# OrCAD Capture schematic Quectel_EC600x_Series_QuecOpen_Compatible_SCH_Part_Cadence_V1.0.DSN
size A1

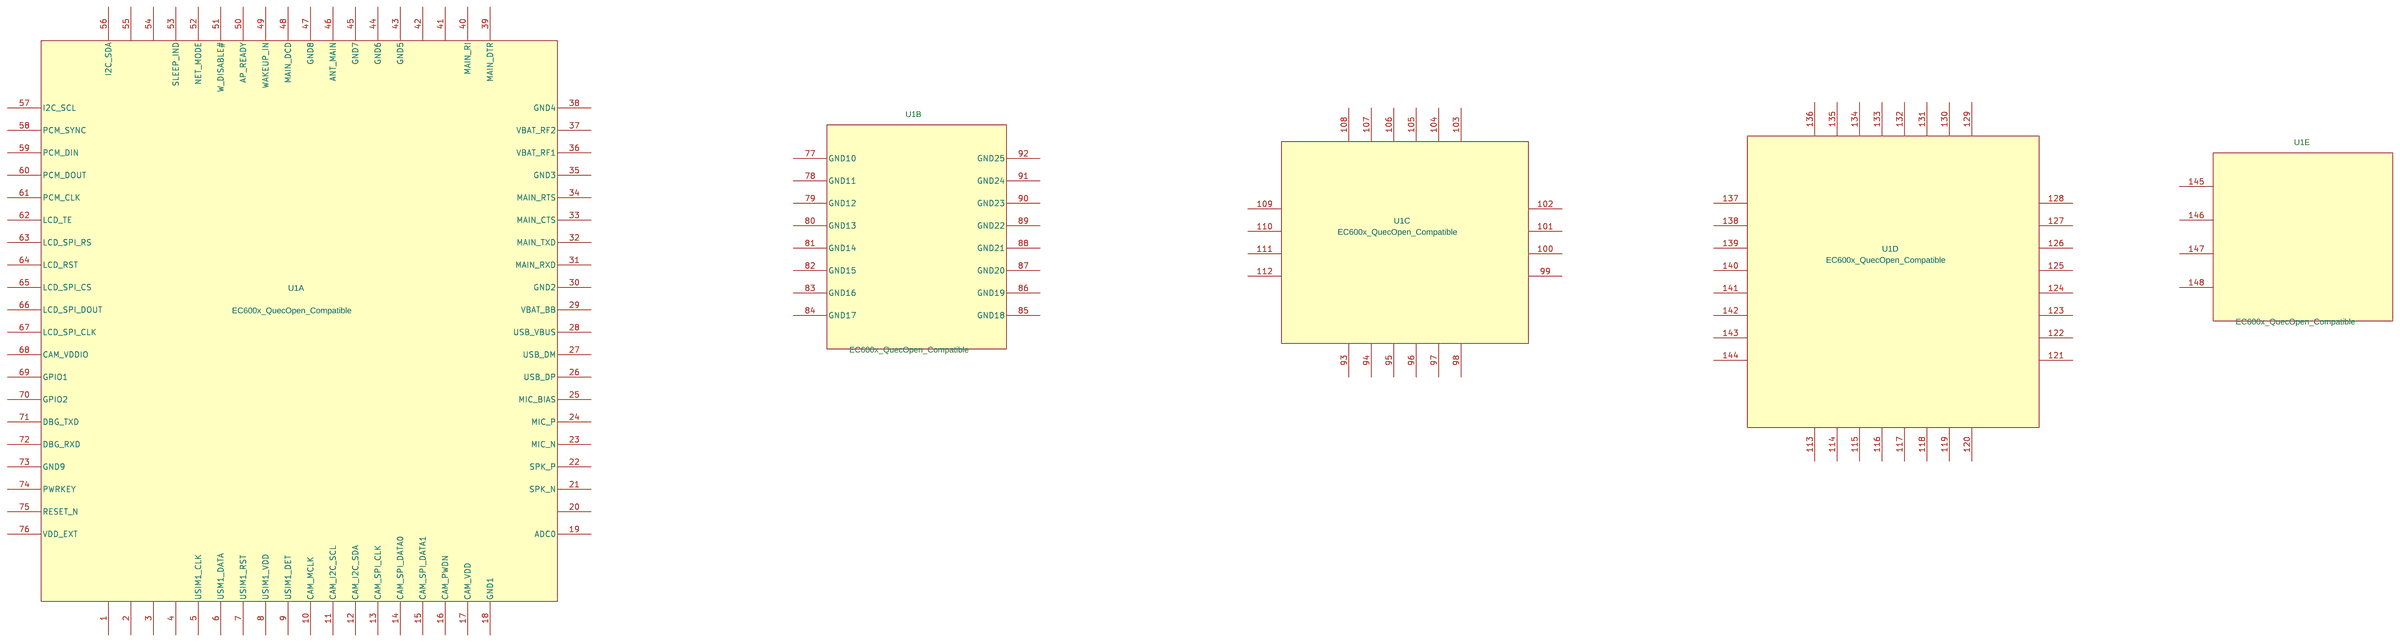
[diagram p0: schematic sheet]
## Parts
U1  EC600x_QuecOpen_Compatible  [EC600x_QuecOpen_Compatible]  (sections A,B,C,D,E)

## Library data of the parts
U1 = EC600x_QuecOpen_Compatible

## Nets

Not connected (* = marked no-connect by the designer): U1 1 2 3 4 5(USIM1_CLK) 6(USM1_DATA) 7(USIM1_RST) 8(USIM1_VDD) 9(USIM1_DET) 10(CAM_MCLK) 11(CAM_I2C_SCL) 12(CAM_I2C_SDA) 13(CAM_SPI_CLK) 14(CAM_SPI_DATA0) 15(CAM_SPI_DATA1) 16(CAM_PWDN) 17(CAM_VDD) 18(GND1) 19(ADC0) 20 21(SPK_N) 22(SPK_P) 23(MIC_N) 24(MIC_P) 25(MIC_BIAS) 26(USB_DP) 27(USB_DM) 28(USB_VBUS) 29(VBAT_BB) 30(GND2) 31(MAIN_RXD) 32(MAIN_TXD) 33(MAIN_CTS) 34(MAIN_RTS) 35(GND3) 36(VBAT_RF1) 37(VBAT_RF2) 38(GND4) 39(MAIN_DTR) 40(MAIN_RI) 41 42 43(GND5) 44(GND6) 45(GND7) 46(ANT_MAIN) 47(GND8) 48(MAIN_DCD) 49(WAKEUP_IN) 50(AP_READY) 51(W_DISABLE#) 52(NET_MODE) 53(SLEEP_IND) 54 55 56(I2C_SDA) 57(I2C_SCL) 58(PCM_SYNC) 59(PCM_DIN) 60(PCM_DOUT) 61(PCM_CLK) 62(LCD_TE) 63(LCD_SPI_RS) 64(LCD_RST) 65(LCD_SPI_CS) 66(LCD_SPI_DOUT) 67(LCD_SPI_CLK) 68(CAM_VDDIO) 69(GPIO1) 70(GPIO2) 71(DBG_TXD) 72(DBG_RXD) 73(GND9) 74(PWRKEY) 75(RESET_N) 76(VDD_EXT) 77(GND10) 78(GND11) 79(GND12) 80(GND13) 81(GND14) 82(GND15) 83(GND16) 84(GND17) 85(GND18) 86(GND19) 87(GND20) 88(GND21) 89(GND22) 90(GND23) 91(GND24) 92(GND25) 93 94 95 96 97 98 99 100 101 102 103 104 105 106 107 108 109 110 111 112 113 114 115 116 117 118 119 120 121 122 123 124 125 126 127 128 129 130 131 132 133 134 135 136 137 138 139 140 141 142 143 144 145 146 147 148
